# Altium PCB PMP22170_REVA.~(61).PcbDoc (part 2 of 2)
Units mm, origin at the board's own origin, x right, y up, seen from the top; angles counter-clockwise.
Board outline 78 x 48 mm, 2 copper layers (Top Layer, Bottom Layer), stack 1.575 mm thick; 75 components, 28 nets, 160 pads, 116 vias.

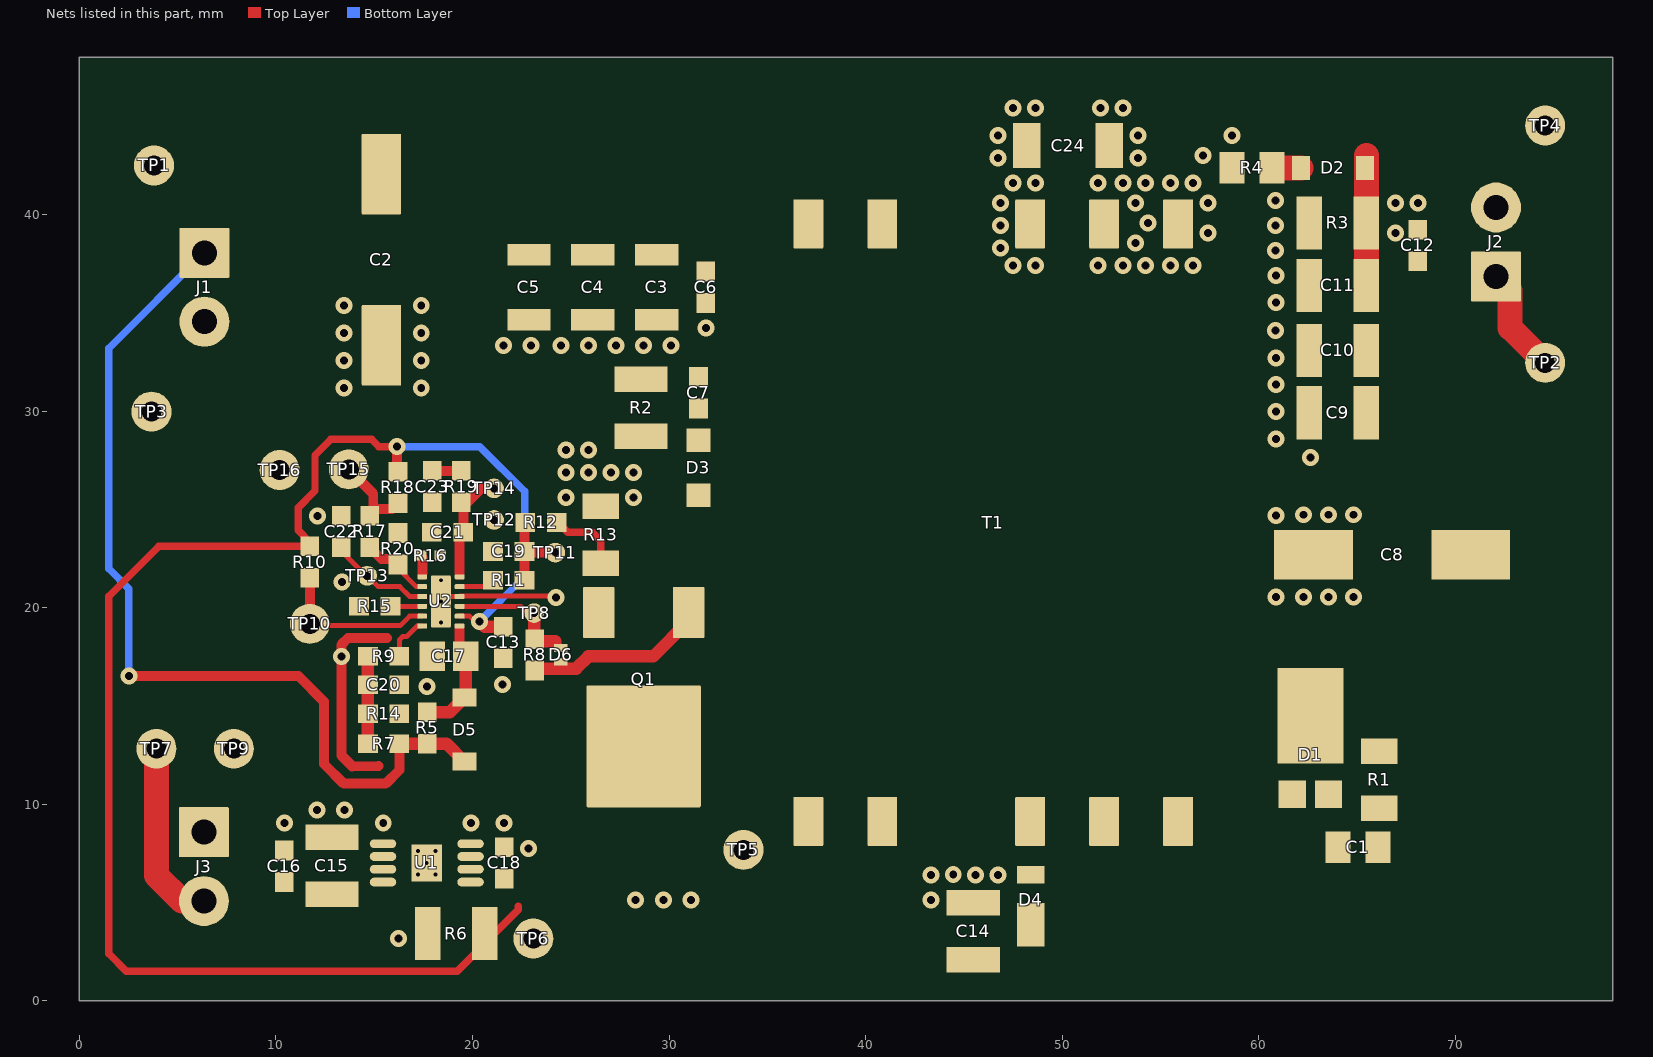
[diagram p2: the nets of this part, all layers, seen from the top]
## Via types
v1: diameter 0.864, hole 0.406, Top Layer to Bottom Layer, 108 vias
v2: diameter 0.5, hole 0.2, Top Layer to Bottom Layer, 8 vias

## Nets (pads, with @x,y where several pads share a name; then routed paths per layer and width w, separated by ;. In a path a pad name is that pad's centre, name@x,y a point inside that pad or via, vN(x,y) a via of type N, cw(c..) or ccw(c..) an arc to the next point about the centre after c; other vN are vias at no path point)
GND: C2.1 C3.2 C4.2 C5.2 C6.2 C13.2 C14.2 C15.2 C16.2 C17.2 C18.2 C19.2 C20.2 C21.2 C22.2 C23.2 C24.2 J1.2 J3.1 R6.1 R13.1 R14.1 R15.1 R16.1 R20.1 T1.9 TP3.1 TP9.1 TP12.1 TP16.1 U1.3 U1.4 U1.5 U1.6 U1.7 U1.9 U2.4 U2.13@18.404,20.318 | length 16.2
  Top Layer w0.254: v2(18.404,20.318) 18.654,20.568 U2.4@19.354,20.568 19.377,20.591 24.178,20.591 v1(24.247,20.522)
  Top Layer w0.508: 15.231,11.938 13.893,11.936 13.336,12.493 v1(13.336,17.524) 13.336,18.11 13.68,18.453 15.671,18.453
  other v1: 16.256,3.175 28.3,5.146 29.718,5.146 31.115,5.146 43.311,5.146 43.311,6.416 44.454,6.421 45.597,6.416 46.74,6.416 22.86,7.747 10.444,9.044 15.47,9.044 19.92,9.044 21.62,9.044 12.095,9.719 13.492,9.719 17.703,16 21.527,16.1 13.385,21.296 21.105,24.459 12.115,24.671 24.769,25.593 28.198,25.593 24.769,26.863 25.912,26.863 27.055,26.863 28.198,26.863 24.769,28.006 25.912,28.006 13.466,31.181 17.403,31.181 13.466,32.578 17.403,32.578 21.588,33.336 22.985,33.336 24.509,33.336 25.906,33.336 27.309,33.336 28.706,33.336 30.097,33.336 13.466,33.975 17.403,33.975 31.881,34.229 13.466,35.372 17.403,35.372 47.502,37.404 48.645,37.404 46.867,38.293 46.867,39.436 46.867,40.579 47.502,41.595 48.645,41.595 46.74,42.865 46.74,44.008 47.502,45.405 48.645,45.405
  other v2: 17.233,6.423 18.133,6.423 17.683,7.023 17.233,7.623 18.133,7.623 18.404,19.243 18.404,21.393
GND2: C8.2 C9.2 C10.2 C11.2 C12.2 C24.1 J2.2 R3.1 R4.1 T1.7 T1.8 TP4.1
  other v1: 60.868,20.533 62.265,20.533 63.535,20.533 64.805,20.533 60.868,24.693 62.265,24.724 63.535,24.724 64.805,24.724 62.615,27.625 60.868,28.573 60.868,29.97 60.868,31.337 60.868,32.705 60.837,34.102 60.868,35.505 60.868,36.888 51.82,37.404 53.09,37.404 54.233,37.404 55.503,37.404 56.646,37.404 60.837,38.166 53.725,38.547 57.408,39.055 66.933,39.055 60.837,39.436 54.36,39.563 53.725,40.578 57.408,40.579 66.933,40.578 68.076,40.579 60.837,40.706 51.82,41.595 53.09,41.595 54.233,41.595 55.503,41.595 56.646,41.595 53.852,42.865 57.154,42.992 53.852,44.008 58.621,44.008 51.947,45.405 53.09,45.405
NetC1_1: C1.1 R1.1
NetC1_2: C1.2 D1.1 D1.2 T1.5 T1.6
NetC2_2: C2.2 C3.1 C4.1 C5.1 C6.1 C7.1 D5.2 J1.1 R2.2 R5.2 R7.2 T1.11 T1.12 TP1.1 | length 47.2
  Top Layer w0.508: v1(2.535,16.523) 11.156,16.523 12.459,15.22 12.459,12.052 13.464,11.047 15.597,11.047 16.292,11.742 R7.2@16.292,13.078
  Top Layer w0.635: R7.2@16.292,13.078 16.301,13.087 R5.2@17.703,13.087 ; R5.2@17.683,13.067 R5.2@17.703,13.087 ; D5.2@19.608,12.166 18.687,13.087 R5.2@17.703,13.087
  Bottom Layer w0.381: v1(2.535,16.523) 2.535,20.96 1.524,21.971 1.524,33.192 J1.1@6.377,38.045
NetC7_2: C7.2 D3.1 R2.1
NetC8_1: C8.1 C9.1 C10.1 C11.1 C12.1 D1.3 D2.1 J2.1 R1.2 R3.2 TP2.1 | length 12
  Top Layer w1.27: C11.1@65.462,36.388 65.462,42.992 ; J2.1@72.051,36.842 72.775,36.118 72.775,34.229 TP2.1@74.553,32.451
NetC13_1: C13.1 C14.1 C18.1 D4.1 R6.2 R10.1 R18.2 TP6.1 U1.1 U1.2 U2.2 | length 80.7
  Top Layer w0.254: U2.2@19.354,19.568 19.864,19.568 20.13,19.302 v1(20.37,19.302)
  Top Layer w0.381: v1(16.179,28.192) 15.254,28.192 14.873,28.573 12.812,28.573 12,27.761 12,25.947 11.145,25.092 11.145,23.926 11.734,23.337 R10.1@11.734,23.121 11.724,23.111 4.064,23.111 1.524,20.571 1.524,2.413 2.413,1.524 19.229,1.524 22.335,4.63 22.335,4.826
  Top Layer w0.508: v1(16.179,28.192) 16.179,26.949 R18.2@16.217,26.911
  Top Layer w0.635: v1(20.37,19.302) 20.636,19.036 C13.1@21.58,19.036
  Bottom Layer w0.381: v1(16.179,28.192) 20.387,28.192 22.653,25.926 22.653,21.585 v1(20.37,19.302)
NetC15_1: C15.1 C16.1 J3.2 TP7.1 U1.8 | length 9.4
  Top Layer w1.27: TP7.1@3.937,12.827 3.937,6.373 5.231,5.08 J3.2@6.35,5.08
NetC17_1: C17.1 D5.1 R5.1 U2.1 | length 6
  Top Layer w0.254: 19.354,18.921 U2.1@19.354,19.068
  Top Layer w0.508: 19.354,18.921 19.354,17.826 C17.1@19.657,17.523
  Top Layer w0.635: R5.1@17.703,14.687 18.855,14.687 D5.1@19.608,15.441 19.657,15.49 C17.1@19.657,17.523
NetC19_1: C19.1 R11.2 R12.1 TP11.1 | length 4.5
  Top Layer w0.508: R11.2@22.653,21.393 C19.1@22.653,22.858 ; R12.1@22.685,24.332 22.653,24.301 C19.1@22.653,22.858 ; v1(24.217,22.796) 22.715,22.796 C19.1@22.653,22.858
NetC20_1: C20.1 R7.1 R9.1 R14.2 | length 4.4
  Top Layer w0.635: R7.1@14.692,13.078 C20.1@14.692,16.076 R9.1@14.692,17.524
NetC21_1: C21.1 R19.2 TP14.1 U2.6 | length 5.9
  Top Layer w0.254: U2.6@19.354,21.568 19.354,21.768
  Top Layer w0.508: 19.354,21.768 19.354,23.646 C21.1@19.545,23.836 19.545,25.259 R19.2@19.443,25.36 19.749,25.36 20.457,26.068 v1(21.105,26.068)
NetC22_1: C22.1 TP13.1 U2.9 | length 5.3
  Top Layer w0.254: C22.1@13.336,23.071 13.336,22.878 14.593,21.621 v1(14.655,21.621) 15.208,21.068 16.311,21.068 16.811,20.568 U2.9@17.454,20.568
NetC23_1: C23.1 R19.1 | length 1.5
  Top Layer w0.508: C23.1@17.957,26.96 R19.1@19.443,26.96
NetD2_2: D2.2 R4.2 | length 1.5
  Top Layer w1.27: R4.2@60.653,42.357 D2.2@62.124,42.357
NetD3_2: D3.2 Q1.2 T1.1 T1.2 TP5.1
NetD4_2: D4.2 T1.4
NetD6_1: D6.1 R8.2 TP8.1 U2.3 | length 6.8
  Top Layer w0.254: U2.3@19.354,20.068 22.472,20.068 22.817,19.723 v1(23.142,19.723)
  Top Layer w0.381: 24.217,18.301 D6.1@24.455,17.98
  Top Layer w0.635: v1(23.142,19.723) 23.142,18.431 R8.2@23.172,18.401 23.272,18.301 24.217,18.301
NetD6_2: D6.2 Q1.1 R8.1 | length 9.3
  Top Layer w0.635: R8.1@23.172,16.801 23.272,16.901 25.283,16.901 25.905,17.523 29.199,17.523 30.995,19.319 Q1.1@30.995,19.75
NetQ1_3: Q1.3 R12.2 R13.2 | length 3.8
  Top Layer w0.381: R12.2@24.285,24.332 24.539,24.078 24.6,24.078 24.854,23.824 26.1,23.824 26.533,23.392 R13.2@26.533,22.268
NetR9_2: R9.2 U2.12 | length 2.3
  Top Layer w0.254: R9.2@16.292,17.524 16.292,18.365 16.45,18.523 16.651,18.523 17.196,19.068 U2.12@17.454,19.068
NetR11_1: R11.1 U2.5 | length 1.8
  Top Layer w0.254: U2.5@19.354,21.068 20.728,21.068 R11.1@21.053,21.393
NetR15_2: R15.2 U2.10 | length 1.6
  Top Layer w0.254: R15.2@15.836,20.068 U2.10@17.454,20.068
NetR16_2: R16.2 U2.7 | length 1.1
  Top Layer w0.254: U2.7@17.454,21.568 17.454,21.768
  Top Layer w0.508: R16.2@17.37,22.646 17.454,22.562 17.454,21.768
NetR17_1: R17.1 R18.1 TP15.1 | length 4.3
  Top Layer w0.508: TP15.1@13.717,27.035 14.962,25.791 14.962,25.181 R17.1@15.125,25.017 ; R17.1@14.782,24.674 R17.1@15.125,25.017 ; R18.1@16.217,25.311 15.924,25.017 R17.1@15.125,25.017
NetR17_2: R17.2 R20.2 U2.8 | length 3.6
  Top Layer w0.254: R20.2@16.217,22.196 16.217,21.997 17.146,21.068 U2.8@17.454,21.068
  Top Layer w0.508: R17.2@14.782,23.074 15.379,22.477 15.936,22.477 R20.2@16.217,22.196
PG: R10.2 TP10.1 U2.11 | length 8.3
  Top Layer w0.254: TP10.1@11.734,19.175 11.822,19.087 16.33,19.087 16.811,19.568 U2.11@17.454,19.568
  Top Layer w0.508: TP10.1@11.734,19.175 R10.2@11.734,21.521
pads on no net: U2.13@18.404,19.633 U2.13@18.404,21.003

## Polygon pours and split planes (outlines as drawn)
GND on Top Layer "TOP_LAYER_GND_P056" (solid, remove dead copper, pour order 56): 0,47.9 0.1,48 49.1,48 49.1,0 0,0
GND2 on Top Layer "TOP_LAYER_GND2_P050" (solid, remove dead copper, pour order 50): 51.4,48 51.4,0 78,0 78,48
NetC13_1 on Top Layer "TOP_LAYER_NETC13_1_P048" (solid, remove dead copper, pour order 48): 19.181,4.384 19.181,6.853 21.15,6.853 21.272,6.731 22.095,6.731 22.095,6.267 23.114,5.248 22.864,4.998 22.709,4.998 22.095,4.384
NetC8_1 on Top Layer "TOP_LAYER_NETC8_1_P046" (solid, remove dead copper, pour order 46): 60.868,12.004 60.964,12.1 60.964,18.862 61.726,19.624 65.049,19.624 65.78,20.355 65.79,24.989 64.805,25.974 64.805,37.494 65.477,38.166 66.975,38.166 73.283,38.166 73.283,34.921 72.902,34.54 69.911,34.54 69.092,33.721 69.092,29.657 72.775,25.974 72.775,14.544 70.235,12.004
NetC1_1 on Top Layer "TOP_LAYER_NETC1_1_P042" (solid, remove dead copper, pour order 42): 65.155,6.67 65.536,6.289 66.844,6.289 67.283,6.728 67.283,11.519 67.051,11.75 65.409,11.75 65.155,11.496
NetC1_2 on Top Layer "TOP_LAYER_NETC1_2_P040" (solid, remove dead copper, pour order 40): 51.312,6.797 51.82,6.289 64.266,6.289 64.647,6.67 64.64,6.677 64.64,11.445 64.266,11.819 60.641,11.819 59.359,13.1 52.661,13.1 51.312,11.75
NetC8_1 on Top Layer "TOP_LAYER_NETC8_1_P038" (solid, remove dead copper, pour order 38): 71.886,9.21
NetC13_1 on Top Layer "TOP_LAYER_NETC13_1_P034" (solid, remove dead copper, pour order 34): 49.153,4.953 47.629,4.953 46.629,3.953 24.417,3.953 22.787,5.583 19.181,5.583 19.181,1.651 19.369,1.463 49.356,1.463 49.356,4.791
NetD4_2 on Top Layer "TOP_LAYER_NETD4_2_P032" (solid, remove dead copper, pour order 32): 47.387,6.276 47.387,7.165 46.867,7.686 46.867,10.48 47.121,10.734 48.772,10.734 49.153,10.353 49.153,6.035 49.026,5.908 47.756,5.908
GND on Top Layer "TOP_LAYER_GND_P030" (solid, remove dead copper, pour order 30): 43.057,6.924 42.168,6.035 25.559,6.035 23.273,8.321 22.356,8.321 22.356,6.518 24.49,4.384 46.848,4.384 47.212,4.748 47.212,6.586 46.994,6.804 46.873,6.924
GND on Top Layer "TOP_LAYER_GND_P028" (solid, remove dead copper, pour order 28): 46.74,7.178
NetD3_2 on Top Layer "TOP_LAYER_NETD3_2_P026" (solid, remove dead copper, pour order 26): 25.305,7.051 24.035,8.321 24.035,14.07 26.54,16.576 29.829,16.576 30.778,17.524 31.887,17.524 32.971,18.608 32.971,22.217 30.865,24.323 30.865,26.355 42.422,26.355 45.47,23.307 45.47,7.686 45.216,7.432 42.803,7.432 41.792,6.421 25.905,6.421
NetC7_2 on Top Layer "TOP_LAYER_NETC7_2_P024" (solid, remove dead copper, pour order 24): 27.229,30.204 27.698,30.673 32.306,30.673 32.602,30.377 32.602,27.457 32.262,27.117 29.087,27.117 28.071,28.133 27.229,28.133
NetC2_2 on Top Layer "TOP_LAYER_NETC2_2_P020" (solid, remove dead copper, pour order 20): 16.387,45.024 44.581,45.024 45.47,44.135 45.47,33.975 42.422,30.927 27.229,30.927 27.182,30.974 27.182,32.323 30.516,32.323 31.529,33.336 32.459,33.336 32.971,33.848 32.971,35.968 32.643,36.296 17.476,36.295 16.367,37.404
NetC2_2 on Top Layer "TOP_LAYER_NETC2_2_P018" (solid, remove dead copper, pour order 18): 15.257,45.035 41.025,45.035
NetC2_2 on Top Layer "TOP_LAYER_NETC2_2_P016" (solid, remove dead copper, pour order 16): 1.655,41.722
NetC2_2 on Top Layer "TOP_LAYER_NETC2_2_P014" (solid, remove dead copper, pour order 14): 3.179,36.295 32.351,36.295 32.352,36.296 32.352,38.965 31.627,39.69 22.737,39.69 17.391,45.035 3.317,45.035 2.417,44.135 2.417,37.023
NetQ1_3 on Top Layer "TOP_LAYER_NETQ1_3_P012" (solid, remove dead copper, pour order 12): 27.639,18.453 27.803,18.617 27.803,22.808 27.676,22.935 25.415,22.935 25.276,22.796 25.263,22.796 25.263,18.676 25.486,18.453
NetQ1_3 on Top Layer "TOP_LAYER_NETQ1_3_P010" (solid, remove dead copper, pour order 10): 26.435,19.75
NetC15_1 on Top Layer "TOP_LAYER_NETC15_1_P008" (solid, remove dead copper, pour order 8): 16.183,6.202 16.183,4.435 14.67,2.921 3.6,2.921 3.6,6.244 4.191,6.835 13.749,6.835 14.207,6.377 16.001,6.385
NetC13_1 on Top Layer "TOP_LAYER_NETC13_1_P006" (solid, remove dead copper, pour order 6): 22.636,4.726
GND on Bottom Layer "BOTTOM_LAYER_GND_P054" (solid, remove dead copper, pour order 54): 49.1,0 49.1,48 0,48 0,0
GND2 on Bottom Layer "BOTTOM_LAYER_GND2_P052" (solid, remove dead copper, pour order 52): 51.4,48 51.4,0 78,0 78,48

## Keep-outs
Keep-Out Layer:
  text ".Layer_Name" at 14.656,-21.806 h1.52

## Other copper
Top Layer:
  text ".Layer_Name" at 14.656,-21.806 h1.52
Bottom Layer:
  text ".Layer_Name" at 14.656,-21.806 h1.52

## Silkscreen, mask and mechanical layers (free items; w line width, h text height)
Top Overlay:
  lines w0.229: 20.928,16.4 20.929,16.4 21.2,16.129 21.2,13.337 21.493,13
  text "'.PRJ_Number'.PCB_Rev" at 22.543,45.405 h2.75
  text "VIN" at 0.6,39.9 h1.85 r270
  text "GND2" at 77.6,39 h1.85 r90
  text "GND" at 0.6,36.1 h1.85 r270
  text "VOUT2" at 77.6,32.8 h1.85 r90
  text "GND" at 0.6,10.9 h1.85 r270
  text "VOUT1" at 0.6,6.698 h1.85 r270
  text ".Layer_Name" at 14.656,-21.806 h1.52
Bottom Overlay:
  text ".Layer_Name" at 14.656,-21.806 h1.52
Top Paste:
  text ".Layer_Name" at 14.656,-21.806 h1.52
Bottom Paste:
  text ".Layer_Name" at 14.656,-21.806 h1.52
Top Solder:
  text ".Layer_Name" at 14.656,-21.806 h1.52
  text ".Layer_Name" at 14.656,-21.806 h1.52
Bottom Solder:
  text ".Layer_Name" at 14.656,-21.806 h1.52
Drill Guide:
  text ".Layer_Name" at 14.656,-21.806 h1.52
M1 Board Outline:
  lines w0.229: 0,0 78,0 78,48 0,48 0,0
  lines w0.254: 0,0 0,48 78,48 78,0 0,0
  text ".Layer_Name" at 14.656,-21.806 h1.52
M2 Board Dimensions:
  rectangle: 0,-6.985 3.175,-3.81
  rectangle: 3.175,-10.16 12.7,-6.985
  lines w0.178: 0,-6.985 25.4,-6.985 ; 3.175,-10.16 3.175,-3.81 ; 6.35,-10.16 6.35,-3.81 ; 12.7,-10.16 12.7,-3.81 ; 19.05,-10.16 19.05,-3.81 ; 0,-10.16 25.4,-10.16 25.4,-3.81 0,-3.81 0,-10.16
  text ".Layer_Name" at 14.656,-21.806 h1.52
M3 3D STEP Top:
  text ".Layer_Name" at 14.656,-21.806 h1.52
M4 3D STEP Bottom:
  text ".Layer_Name" at 14.656,-21.806 h1.52
M5 Assembly Top:
  lines w0.127: 30.484,28.768 32.497,28.768 ; 30.484,25.212 30.484,29.022 32.497,29.022 32.497,25.212 30.484,25.212
  lines w0.229: 30.615,28.895 32.37,28.895
  lines w0.254: -7.417,-23.626 160.223,-23.626 ; -7.417,-18.462 160.274,-18.462 ; -7.417,-13.297 -7.417,-28.791 94.31,-28.791 160.274,-28.791 160.274,-13.297 -7.404,-13.297 -7.404,-28.791 32.614,-28.791 ; 55.194,-28.791 55.194,-13.297 ; 87.376,-18.462 87.376,-13.297 ; 108.712,-18.462 108.712,-13.297 ; 124.511,-28.956 124.511,-23.804
  text "COMPONENTS MARKED 'DNP' SHOULD NOT BE POPULATED." at 29.299,-8.09 h1.52
  text "ASSEMBLY VARIANT:" at 29.286,-11.024 h1.52
  text ".VariantName" at 55.601,-11.024 h1.52
  text "PCB VIEWED FROM TOP SIDE" at -5.804,-16.654 h1.52
  text "BOARD #:" at 57.099,-16.654 h1.52
  text ".PRJ_Number" at 70.955,-16.654 h1.52
  text "REV:" at 92.405,-16.654 h1.52
  text ".PCB_Rev" at 99.809,-16.654 h1.52
  text "SVN REV:" at 113.69,-16.654 h1.52
  text ".VersionControl_RevNumber" at 126.543,-16.654 h1.52
  text "TID #:" at 57.099,-21.819 h1.52
  text ".TID" at 70.955,-21.819 h1.52
  text "PLOT NAME =" at -5.804,-27.034 h1.52
  text ".plot_File_Name" at 14.656,-27.034 h1.52
  text "GENERATED    :" at 57.15,-27.034 h1.52
  text ".Print_Date" at 79.235,-27.034 h1.52
  text ".Print_Time" at 97.752,-27.034 h1.52
  text "TEXAS INSTRUMENTS" at 129.87,-27.034 h1.52
M6 Assembly Bottom:
  lines w0.254: -7.429,-18.474 160.261,-18.474 ; -7.379,-23.639 160.261,-23.639 ; 28.334,-28.969 28.334,-23.817 ; 44.133,-18.474 44.133,-13.31 ; 65.468,-18.474 65.468,-13.31 ; 97.65,-28.804 97.65,-13.31 ; 120.231,-28.804 160.249,-28.804 160.249,-13.31 -7.429,-13.31 -7.429,-28.804 58.534,-28.804 160.261,-28.804 160.261,-13.31
  text "COMPONENTS MARKED 'DNP' SHOULD NOT BE POPULATED." at 154.991,-8.077 h1.52
  text ".VariantName" at 128.473,-11.024 h1.52
  text "ASSEMBLY VARIANT:" at 154.864,-11.024 h1.52
  text ".VersionControl_RevNumber" at 26.302,-16.667 h1.52
  text "SVN REV:" at 39.154,-16.667 h1.52
  text ".PCB_Rev" at 53.035,-16.667 h1.52
  text "REV:" at 60.439,-16.667 h1.52
  text ".PRJ_Number" at 81.89,-16.667 h1.52
  text "BOARD #:" at 95.745,-16.667 h1.52
  text "PCB VIEWED FROM BOTTOM SIDE" at 158.648,-16.667 h1.52
  text ".TID" at 81.89,-21.831 h1.52
  text "TID #:" at 95.745,-21.831 h1.52
  text "TEXAS INSTRUMENTS" at 22.974,-27.047 h1.52
  text ".Print_Time" at 55.093,-27.047 h1.52
  text ".Print_Date" at 73.609,-27.047 h1.52
  text "GENERATED    :" at 95.694,-27.047 h1.52
  text ".plot_File_Name" at 138.189,-27.047 h1.52
  text "PLOT NAME =" at 158.648,-27.047 h1.52
M9 Title Sheet:
  drawing of 57 lines, arcs and shapes, not listed
  text "1" at 18.792,204.127 h1.78
  text "2" at 82.182,204.127 h1.78
  text "3" at 145.411,204.127 h1.78
  text "4" at 209.08,204.127 h1.78
  text "5" at 272.555,204.127 h1.78
  text "6" at 336.182,204.127 h1.78
  text "A" at -10.579,175.095 h1.78
  text "A" at 365.341,175.095 h1.78
  text "B" at -10.579,114.643 h1.78
  text "B" at 365.341,114.643 h1.78
  text "C" at -10.579,54.318 h1.78
  text "C" at 365.341,54.318 h1.78
  text "PROJECT TITLE:" at 288.125,7.048 h1.14
  text ".PRJ_Title" at 289.395,3.662 h1.78
  text "DESIGNED FOR:" at 288.125,-0.597 h1.14
  text ".PRJ_Customer" at 289.395,-4.153 h1.78
  text "D" at -10.579,-5.88 h1.78
  text "D" at 365.341,-5.88 h1.78
  text "FILE NAME:" at 288.125,-8.217 h1.14
  text ".PCB_File_Name_No_Path" at 289.395,-11.265 h1.78
  text "Texas Instruments (TI) and/or its licensors do not warrant the accuracy or completeness of this specification" at 161.9,-15.376 h1.14
  text "ENGINEER:" at 288.125,-15.583 h1.14
  text "LAYOUT BY:" at 326.352,-15.583 h1.14
  text "or any information contained therein. TI and/or its licensors do not warrant that this design will meet" at 160.757,-18.237 h1.14
  text ".PRJ_Engineer" at 289.395,-19.52 h1.78
  text ".PCB_Layout" at 327.635,-19.52 h1.78
  text "the specifications, will be suitable for your application or fit for any particular purpose, or will operate in" at 160.757,-21.099 h1.14
  text ".Layer_Name" at 14.656,-21.806 h1.52
  text "ALTIUM DESIGNER VERSION:" at 326.352,-23.457 h1.14
  text "an implementation. TI and/or its licensors do not warrant that the design is production worthy. You should" at 160.757,-23.961 h1.14
  text "completely validate and test your design implementation to confirm the system functionality for your application." at 161.9,-26.822 h1.14
  text ".print_Scale" at 289.395,-26.843 h1.78
  text ".Application_BuildNumber" at 327.635,-26.843 h1.78
  text "1" at 18.792,-32.093 h1.78
  text "2" at 82.182,-32.093 h1.78
  text "3" at 145.411,-32.093 h1.78
  text "4" at 209.08,-32.093 h1.78
  text "5" at 272.555,-32.093 h1.78
  text "6" at 336.182,-32.093 h1.78
M10 Fab Notes:
  drawing of 189 lines, arcs and shapes, not listed
  text "DESIGN INFORMATION" at 314.503,161.447 h1.52
  text "MIN. TRACK WIDTH:" at 298.131,158.091 h1.52
  text "8" at 325.976,158.091 h1.52
  text "MIL" at 329.907,158.091 h1.52
  text "MIN. CLEARANCE:" at 298.131,154.938 h1.52
  text "0.2" at 324.452,154.938 h1.52
  text "mm" at 329.907,154.938 h1.52
  text "MIN. VIA PAD SIZE:" at 298.131,151.785 h1.52
  text "24" at 325.214,151.785 h1.52
  text "MIL" at 329.907,151.785 h1.52
  text "0.05mm (2MIL)" at 315.784,148.486 h1.52
  text "MINIMUM ANNULAR RING" at 289.769,148.277 h1.52
  text "EXTERNAL" at 333.768,148.277 h1.52
  text "PER" at 294.849,145.48 h1.52
  text "IPC-D-275 CLASS 2 LEVEL C" at 300.437,145.48 h1.52
  text "MIL, HOLES" at 338.238,142.928 h1.52
  text "+/-" at 328.27,142.709 h1.52
  text "+/-" at 349.961,142.709 h1.52
  text "REGISTRATION TOLERANCES:" at 289.769,142.682 h1.52
  text "METAL" at 320.243,142.682 h1.52
  text "5" at 334.879,142.683 h1.52
  text "3" at 356.037,142.683 h1.52
  text "MIL" at 358.99,142.682 h1.52
  text "HOLE SIZE TOLERANCE (UNLESS OTHERWISE SPECIFIED):" at 289.769,140.185 h1.52
  text "+/-" at 349.961,140.112 h1.52
  text "3" at 356.037,140.085 h1.52
  text "MIL" at 358.99,140.085 h1.52
  text "MATERIAL:" at 287.87,136.589 h1.52
  text "FR-4 High Tg" at 312.926,133.324 h1.52
  text "X" at 309.257,133.122 h1.52
  text "FR-408" at 298.563,133.007 h1.52
  text "OTHER" at 336.358,133.007 h1.52
  text "62 MIL (1.6mm) +/-10%" at 306.694,129.374 h1.52
  text "X" at 303.643,129.312 h1.52
  text "THICKNESS:" at 289.769,129.165 h1.52
  text "OTHER" at 339.33,129.165 h1.52
  text "TOLERANCE:" at 289.769,125.652 h1.52
  text "X" at 311.314,125.652 h1.52
  text "ANSI IPC-6012 TYPE 3 CLASS 2" at 315.836,125.652 h1.52
  text "OTHER +/-" at 315.835,121.989 h1.52
  text "BOW & TWIST:" at 289.769,118.302 h1.52
  text "X" at 311.314,118.302 h1.52
  text "ANSI IPC-6012 TYPE 3 CLASS 2" at 315.836,118.302 h1.52
  text "OTHER +/-" at 315.835,114.576 h1.52
  text "DRILLING:" at 287.87,111.258 h1.52
  text "NC_DRILL FILES" at 332.599,108.586 h1.52
  text "REFERENCE:" at 289.769,108.486 h1.52
  text "X" at 306.463,108.484 h1.52
  text "AS SHOWN" at 310.984,108.486 h1.52
  text "X" at 329.348,108.486 h1.52
  text "OTHER" at 340.168,104.873 h1.52
  text "PTH COPPER THICKNESS:" at 289.761,104.783 h1.52
  text "X" at 318.697,104.783 h1.52
  text "20-30 um" at 321.948,104.783 h1.52
  text "BOARD FINISH:" at 287.87,101.034 h1.52
  text "SILKSCREEN:" at 291.812,98.237 h1.52
  text "X" at 316.14,98.237 h1.52
  text "TOP" at 319.112,98.237 h1.52
  text "X" at 329.094,98.237 h1.52
  text "BOTTOM" at 332.091,98.237 h1.52
  text "SILKSCREEN COLOR:" at 291.812,94.295 h1.52
  text "X" at 316.115,94.295 h1.52
  text "WHITE" at 319.112,94.295 h1.52
  text "OTHER" at 332.091,94.295 h1.52
  text "X" at 319.442,90.652 h1.52
  text "GREEN" at 322.439,90.652 h1.52
  text "OTHER" at 338.136,90.652 h1.52
  text "SOLDER RESIST COLOR:" at 291.812,90.477 h1.52
  text "X" at 319.442,86.734 h1.52
  text "MATTE" at 322.439,86.734 h1.52
  text "SEMI-GLOSS" at 338.125,86.717 h1.52
  text "IMMERSION GOLD (ENIG)" at 314.819,82.345 h1.52
  text "ENEPIG" at 348.793,82.162 h1.52
  text "SURFACE FINISH:" at 287.87,82.136 h1.52
  text "X" at 310.298,82.136 h1.52
  text "IMM. TIN/SILVER OR EQUIV" at 296.24,78.649 h1.52
  text "OTHER" at 332.599,78.549 h1.52
  text "ARRAY/PANEL:" at 287.87,74.602 h1.52
  text "CUT AND TRIM PER M1 BOARD OUTLINE" at 314.819,74.393 h1.52
  text "N.C. ROUTE" at 314.819,70.94 h1.52
  text "X" at 332.295,70.94 h1.52
  text "V. SCORE" at 336.816,70.94 h1.52
  text "CERTIFICATION:" at 287.87,67.66 h1.52
  text "MATERIALS AND WORKMANSHIP FOR ALL PCBS" at 306.285,67.66 h1.52
  text "TO MEET OR EXCEED THE REQUIREMENTS OF:" at 306.285,65.271 h1.52
  text "X" at 297.078,62.003 h1.52
  text "ANSI IPC-A-600F CLASS ->" at 300.329,62.003 h1.52
  text "X" at 342.188,62.003 h1.52
  text "2" at 344.982,62.003 h1.52
  text "1" at 336.981,61.965 h1.52
  text "3" at 353.973,61.965 h1.52
  text "X" at 317.702,58.252 h1.52
  text "RoHS" at 320.953,58.252 h1.52
  text "OTHER" at 337.321,58.252 h1.52
  text "PER ORDER" at 347.407,58.252 h1.52
  text "ALL BOARDS MUST MEET OR EXCEED UL94-V0 REQUIREMENTS." at 288.569,54.345 h1.52
  text "PCB MUST BEAR THE UL94V-0 UL REGISTERED MATERIAL ID NUMBER" at 288.569,51.397 h1.52
  text "ADDITIONAL REQUIREMENTS:" at 287.87,47.094 h1.52
  text "MICROSECTION:" at 289.769,44.373 h1.52
  text "YES" at 312.775,44.373 h1.52
  text "REQUIRED" at 334.657,40.707 h1.52
  text "BARE BOARD ELEC. TEST:" at 289.769,40.634 h1.52
  text "NONE" at 322.935,40.634 h1.52
  text "X" at 331.66,40.634 h1.52
  text "PER ORDER" at 349.693,40.634 h1.52
  text "XX MIL VIAS REQUIRE NON-CONDUCTIVE FILL AND PLANARIZE" at 294.04,35.428 h1.5
  text "XX MIL VIAS REQUIRE CONDUCTIVE FILL AND PLANARIZE" at 294.243,32.787 h1.52
  text "OUTER XX MIL TRACES REQUIRE 50 OHM SINGLE-ENDED IMPEDANCE" at 294.218,28.637 h1.47
  text "LAYER 2 & 3 (INNER LAYERS) XX MIL WIDE, XX MIL SPACE / TRACES REQUIRE 100 OHM DIFFERENTIAL IMPEDANCE" at 294.015,22.65 h1.52
  text ".Layer_Name" at 14.656,-21.806 h1.52
M11 Gerber Information:
  lines w0.254: -7.417,-23.626 160.223,-23.626 ; -7.417,-18.462 160.274,-18.462 ; -7.417,-13.297 -7.417,-28.791 94.31,-28.791 160.274,-28.791 160.274,-13.297 -7.404,-13.297 -7.404,-28.791 32.614,-28.791 ; 55.194,-28.791 55.194,-13.297 ; 87.376,-18.462 87.376,-13.297 ; 108.712,-18.462 108.712,-13.297 ; 124.511,-28.956 124.511,-23.804
  text "ALL ARTWORK VIEWED FROM TOP SIDE" at -5.804,-16.654 h1.52
  text "BOARD #:" at 57.099,-16.654 h1.52
  text ".PRJ_Number" at 70.955,-16.654 h1.52
  text "REV:" at 92.405,-16.654 h1.52
  text ".PCB_Rev" at 99.809,-16.654 h1.52
  text "SVN REV:" at 113.69,-16.654 h1.52
  text ".VersionControl_RevNumber" at 126.543,-16.654 h1.52
  text "LAYER NAME =" at -5.804,-21.806 h1.52
  text "TID #:" at 57.099,-21.819 h1.52
  text ".TID" at 70.955,-21.819 h1.52
  text "PLOT NAME =" at -5.804,-27.034 h1.52
  text ".plot_File_Name" at 14.656,-27.034 h1.52
  text "GENERATED    :" at 57.15,-27.034 h1.52
  text ".Print_Date" at 79.235,-27.034 h1.52
  text ".Print_Time" at 97.752,-27.034 h1.52
  text "TEXAS INSTRUMENTS" at 129.87,-27.034 h1.52
M12 Stackup:
  drawing of 191 lines, arcs and shapes, not listed
  text "Layer" at 249.215,197.737 h1.52
  text "Name" at 259.626,197.737 h1.52
  text "Material" at 283.242,197.737 h1.52
  text "Thickness" at 305.08,197.737 h1.52
  text "Constant" at 321.586,197.737 h1.52
  text "Board Layer Stack" at 336.06,197.737 h1.52
  text "1" at 249.215,194.689 h1.52
  text "Top Overlay" at 259.626,194.689 h1.52
  text "2" at 249.215,191.641 h1.52
  text "Top Solder" at 259.626,191.641 h1.52
  text "Solder Resist" at 283.242,191.641 h1.52
  text "0.40mil" at 305.08,191.641 h1.52
  text "3.5" at 321.586,191.641 h1.52
  text "3" at 249.215,188.593 h1.52
  text "Top Layer" at 259.626,188.593 h1.52
  text "Copper" at 283.242,188.593 h1.52
  text "1.40mil" at 305.08,188.593 h1.52
  text "4" at 249.215,185.545 h1.52
  text "Dielectric1" at 259.626,185.545 h1.52
  text "FR-4" at 283.242,185.545 h1.52
  text "59.20mil" at 305.08,185.545 h1.52
  text "4.8" at 321.586,185.545 h1.52
  text "5" at 249.215,182.497 h1.52
  text "Bottom Layer" at 259.626,182.497 h1.52
  text "Copper" at 283.242,182.497 h1.52
  text "1.40mil" at 305.08,182.497 h1.52
  text "6" at 249.215,179.449 h1.52
  text "Bottom Solder" at 259.626,179.449 h1.52
  text "Solder Resist" at 283.242,179.449 h1.52
  text "0.40mil" at 305.08,179.449 h1.52
  text "3.5" at 321.586,179.449 h1.52
  text "7" at 249.215,176.401 h1.52
  text "Bottom Overlay" at 259.626,176.401 h1.52
  text ".Layer_Name" at 14.656,-21.806 h1.52
M13 Component Bodies Top:
  text ".Layer_Name" at 14.656,-21.806 h1.52
M14 Component Bodies Bottom:
  text ".Layer_Name" at 14.656,-21.806 h1.52
M15 Courtyards Top:
  text ".Layer_Name" at 14.656,-21.806 h1.52
M16 Courtyards Bottom:
  text ".Layer_Name" at 14.656,-21.806 h1.52
Drill Drawing:
  circle w0.254: c136.238,81.177 r0.702
  lines w0.254: 135.537,75.564 136.94,75.564 136.238,74.16 135.537,75.564 ; 135.537,77.318 136.94,77.318 136.94,78.721 135.537,78.721 135.537,77.318 ; 135.537,83.984 135.888,83.984 136.238,83.633 136.589,83.984 136.94,83.984 136.589,84.335 136.94,84.686 136.589,84.686 136.238,85.037 135.888,84.686 135.537,84.686 135.888,84.335 135.537,83.984
  lines w0.305: 134.264,73.213 216.344,73.213 ; 134.264,85.844 216.344,85.844 ; 142.846,70.055 142.846,89.002 ; 151.279,70.055 151.279,89.002 ; 167.448,70.055 167.448,89.002 ; 174.03,70.055 174.03,89.002 ; 183.559,70.055 183.559,89.002 ; 201.957,70.055 201.957,89.002 ; 134.264,70.055 216.344,70.055 216.344,89.002 134.264,89.002 134.264,70.055
  text "Symbol" at 136.159,86.791 h1.83
  text "Quantity" at 143.793,86.791 h1.83
  text "Finished Hole Size" at 152.226,86.791 h1.83
  text "Plated" at 168.395,86.791 h1.83
  text "Hole Type" at 174.977,86.791 h1.83
  text "Drill Layer Pair" at 184.506,86.791 h1.83
  text "Hole Tolerance" at 202.904,86.791 h1.83
  text "8" at 143.793,83.633 h1.52
  text "7.87mil (0.200mm)" at 152.226,83.633 h1.52
  text "PTH" at 168.395,83.633 h1.52
  text "Round" at 174.977,83.633 h1.52
  text "Top Layer - Bottom Layer" at 184.506,83.633 h1.52
  text "108" at 143.793,80.476 h1.52
  text "16.00mil (0.406mm)" at 152.226,80.476 h1.52
  text "PTH" at 168.395,80.476 h1.52
  text "Round" at 174.977,80.476 h1.52
  text "Top Layer - Bottom Layer" at 184.506,80.476 h1.52
  text "11" at 143.793,77.318 h1.52
  text "40.00mil (1.016mm)" at 152.226,77.318 h1.52
  text "PTH" at 168.395,77.318 h1.52
  text "Round" at 174.977,77.318 h1.52
  text "Top Layer - Bottom Layer" at 184.506,77.318 h1.52
  text "6" at 143.793,74.16 h1.52
  text "50.00mil (1.270mm)" at 152.226,74.16 h1.52
  text "PTH" at 168.395,74.16 h1.52
  text "Round" at 174.977,74.16 h1.52
  text "Top Layer - Bottom Layer" at 184.506,74.16 h1.52
  text "133 Total" at 143.793,71.003 h1.52
  text ".Layer_Name" at 14.656,-21.806 h1.52
M17 Embedded Cavity:
  text ".Layer_Name" at 14.656,-21.806 h1.52
M18 Embedded Assembly:
  text ".Layer_Name" at 14.656,-21.806 h1.52
M19 Embedded Keepout:
  text ".Layer_Name" at 14.656,-21.806 h1.52

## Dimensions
0,-10.16 to 25.4,-10.16 on M2 Board Dimensions
0,0 to 0,48 on M2 Board Dimensions
0,0 to 78,0 on M2 Board Dimensions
